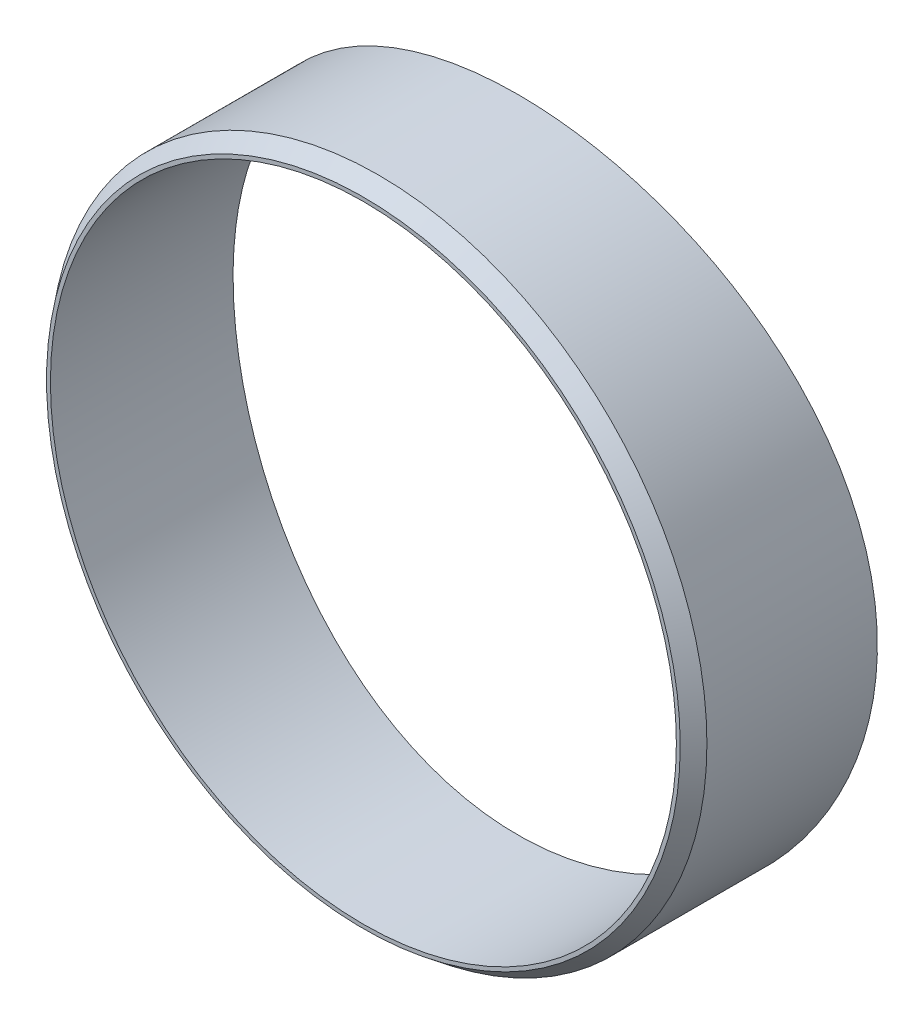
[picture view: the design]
ISO-10303-21;
HEADER;
FILE_DESCRIPTION(('STEP AP214'),'2;1');
FILE_NAME('part.step','',(''),(''),'','','');
FILE_SCHEMA(('AUTOMOTIVE_DESIGN { 1 0 10303 214 1 1 1 1 }'));
ENDSEC;
DATA;
#1=APPLICATION_CONTEXT('core data for automotive mechanical design processes');
#2=APPLICATION_PROTOCOL_DEFINITION('international standard','automotive_design',2000,#1);
#3=PRODUCT_CONTEXT('',#1,'mechanical');
#4=PRODUCT('Part','Part','',(#3));
#5=PRODUCT_RELATED_PRODUCT_CATEGORY('part','',(#4));
#6=PRODUCT_DEFINITION_FORMATION('','',#4);
#7=PRODUCT_DEFINITION_CONTEXT('part definition',#1,'design');
#8=PRODUCT_DEFINITION('design','',#6,#7);
#9=PRODUCT_DEFINITION_SHAPE('','',#8);
#10=(LENGTH_UNIT() NAMED_UNIT(*) SI_UNIT(.MILLI.,.METRE.));
#11=(NAMED_UNIT(*) PLANE_ANGLE_UNIT() SI_UNIT($,.RADIAN.));
#12=(NAMED_UNIT(*) SI_UNIT($,.STERADIAN.) SOLID_ANGLE_UNIT());
#13=UNCERTAINTY_MEASURE_WITH_UNIT(LENGTH_MEASURE(1.E-05),#10,'distance_accuracy_value','');
#14=(GEOMETRIC_REPRESENTATION_CONTEXT(3) GLOBAL_UNCERTAINTY_ASSIGNED_CONTEXT((#13)) GLOBAL_UNIT_ASSIGNED_CONTEXT((#10,
#11,#12)) REPRESENTATION_CONTEXT('',''));
#15=CARTESIAN_POINT('',(0.,0.,0.));
#16=DIRECTION('',(0.,0.,1.));
#17=DIRECTION('',(1.,0.,0.));
#18=AXIS2_PLACEMENT_3D('',#15,#16,#17);
#19=CARTESIAN_POINT('',(0.,0.,63.5));
#20=DIRECTION('',(0.,0.,1.));
#21=DIRECTION('',(1.,0.,0.));
#22=AXIS2_PLACEMENT_3D('',#19,#20,#21);
#23=PLANE('',#22);
#24=CARTESIAN_POINT('',(0.,0.,63.5));
#25=DIRECTION('',(0.,0.,1.));
#26=DIRECTION('',(1.,0.,0.));
#27=AXIS2_PLACEMENT_3D('',#24,#25,#26);
#28=CIRCLE('',#27,128.5875);
#29=CARTESIAN_POINT('',(128.5875,0.,63.5));
#30=VERTEX_POINT('',#29);
#31=EDGE_CURVE('E10',#30,#30,#28,.T.);
#32=ORIENTED_EDGE('',*,*,#31,.F.);
#33=EDGE_LOOP('',(#32));
#34=FACE_BOUND('',#33,.T.);
#35=CARTESIAN_POINT('',(0.,0.,63.5));
#36=DIRECTION('',(0.,0.,1.));
#37=DIRECTION('',(1.,0.,0.));
#38=AXIS2_PLACEMENT_3D('',#35,#36,#37);
#39=CIRCLE('',#38,130.175);
#40=CARTESIAN_POINT('',(130.175,0.,63.5));
#41=VERTEX_POINT('',#40);
#42=EDGE_CURVE('E55',#41,#41,#39,.T.);
#43=ORIENTED_EDGE('',*,*,#42,.T.);
#44=EDGE_LOOP('',(#43));
#45=FACE_BOUND('',#44,.T.);
#46=ADVANCED_FACE('F32',(#34,#45),#23,.T.);
#47=CARTESIAN_POINT('',(0.,0.,63.5));
#48=DIRECTION('',(0.,0.,-1.));
#49=DIRECTION('',(-1.,0.,0.));
#50=AXIS2_PLACEMENT_3D('',#47,#48,#49);
#51=CYLINDRICAL_SURFACE('',#50,134.9375);
#52=CARTESIAN_POINT('',(0.,134.9375,0.));
#53=CARTESIAN_POINT('',(-1.87618329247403,134.937498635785,-6.00693333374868E-07));
#54=CARTESIAN_POINT('',(-3.75243126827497,134.898361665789,-0.00733083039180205));
#55=CARTESIAN_POINT('',(-7.50173863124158,134.741878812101,-0.0366034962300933));
#56=CARTESIAN_POINT('',(-9.3747976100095,134.624523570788,-0.0585476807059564));
#57=CARTESIAN_POINT('',(-13.1149138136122,134.311767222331,-0.116906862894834));
#58=CARTESIAN_POINT('',(-14.9819683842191,134.11633539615,-0.153327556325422));
#59=CARTESIAN_POINT('',(-18.7059824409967,133.647810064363,-0.240384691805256));
#60=CARTESIAN_POINT('',(-20.5629418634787,133.374716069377,-0.291021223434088));
#61=CARTESIAN_POINT('',(-24.2667996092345,132.750836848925,-0.406259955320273));
#62=CARTESIAN_POINT('',(-26.1136735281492,132.399911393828,-0.47088735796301));
#63=CARTESIAN_POINT('',(-29.790668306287,131.621338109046,-0.613601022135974));
#64=CARTESIAN_POINT('',(-31.6207890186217,131.193689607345,-0.691687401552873));
#65=CARTESIAN_POINT('',(-35.2607158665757,130.262578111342,-0.860758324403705));
#66=CARTESIAN_POINT('',(-37.0705252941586,129.759127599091,-0.951740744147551));
#67=CARTESIAN_POINT('',(-40.6671072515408,128.677278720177,-1.14598722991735));
#68=CARTESIAN_POINT('',(-42.4538777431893,128.098873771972,-1.24925237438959));
#69=CARTESIAN_POINT('',(-45.998672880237,126.86908876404,-1.46719036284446));
#70=CARTESIAN_POINT('',(-47.756733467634,126.217809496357,-1.58184742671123));
#71=CARTESIAN_POINT('',(-51.2435747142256,124.842849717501,-1.82189411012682));
#72=CARTESIAN_POINT('',(-52.9723552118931,124.119168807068,-1.94728378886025));
#73=CARTESIAN_POINT('',(-56.3976938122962,122.600729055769,-2.20793264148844));
#74=CARTESIAN_POINT('',(-58.0942512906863,121.805968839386,-2.34319200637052));
#75=CARTESIAN_POINT('',(-61.4522323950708,120.146823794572,-2.62264840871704));
#76=CARTESIAN_POINT('',(-63.1136557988,119.282438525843,-2.7668455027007));
#77=CARTESIAN_POINT('',(-66.3978539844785,117.485980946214,-3.06312421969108));
#78=CARTESIAN_POINT('',(-68.0206448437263,116.553937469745,-3.21520247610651));
#79=CARTESIAN_POINT('',(-71.2257206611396,114.623408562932,-3.52627235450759));
#80=CARTESIAN_POINT('',(-72.8080021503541,113.624917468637,-3.68526456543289));
#81=CARTESIAN_POINT('',(-75.9291359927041,111.563402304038,-4.00904974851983));
#82=CARTESIAN_POINT('',(-77.4679922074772,110.500383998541,-4.17384220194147));
#83=CARTESIAN_POINT('',(-80.5000077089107,108.31146811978,-4.5081327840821));
#84=CARTESIAN_POINT('',(-81.9931626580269,107.185564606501,-4.67763135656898));
#85=CARTESIAN_POINT('',(-84.9468830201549,104.860508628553,-5.02199797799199));
#86=CARTESIAN_POINT('',(-86.4069282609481,103.660700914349,-5.19690408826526));
#87=CARTESIAN_POINT('',(-89.275349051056,101.200845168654,-5.54912934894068));
#88=CARTESIAN_POINT('',(-90.6837186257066,99.940790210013,-5.72644877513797));
#89=CARTESIAN_POINT('',(-93.4462375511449,97.3627192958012,-6.08224595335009));
#90=CARTESIAN_POINT('',(-94.800386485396,96.0447028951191,-6.26072371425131));
#91=CARTESIAN_POINT('',(-97.4520009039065,93.3531196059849,-6.6175692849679));
#92=CARTESIAN_POINT('',(-98.7494728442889,91.979559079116,-6.7959371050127));
#93=CARTESIAN_POINT('',(-101.285971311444,89.1787603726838,-7.15137512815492));
#94=CARTESIAN_POINT('',(-102.524984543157,87.7515101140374,-7.32844502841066));
#95=CARTESIAN_POINT('',(-104.942009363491,84.8461783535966,-7.67998626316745));
#96=CARTESIAN_POINT('',(-106.120026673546,83.3681016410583,-7.8544578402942));
#97=CARTESIAN_POINT('',(-108.413251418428,80.3633498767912,-8.19960590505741));
#98=CARTESIAN_POINT('',(-109.528452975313,78.8366702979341,-8.37028203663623));
#99=CARTESIAN_POINT('',(-111.69388157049,75.7375653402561,-8.70659929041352));
#100=CARTESIAN_POINT('',(-112.744114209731,74.1651439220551,-8.87224084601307));
#101=CARTESIAN_POINT('',(-114.785927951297,70.9644387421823,-9.19861694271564));
#102=CARTESIAN_POINT('',(-115.776977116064,69.335810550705,-9.35930207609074));
#103=CARTESIAN_POINT('',(-117.689473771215,66.0374952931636,-9.6732068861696));
#104=CARTESIAN_POINT('',(-118.610921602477,64.3678084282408,-9.82642659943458));
#105=CARTESIAN_POINT('',(-120.382533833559,60.9902542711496,-10.1242836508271));
#106=CARTESIAN_POINT('',(-121.23269722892,59.2823864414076,-10.2689208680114));
#107=CARTESIAN_POINT('',(-122.860130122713,55.8315017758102,-10.5485460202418));
#108=CARTESIAN_POINT('',(-123.637400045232,54.088485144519,-10.6835340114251));
#109=CARTESIAN_POINT('',(-125.117557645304,50.5704210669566,-10.9428595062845));
#110=CARTESIAN_POINT('',(-125.820447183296,48.7953744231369,-11.0671972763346));
#111=CARTESIAN_POINT('',(-127.150452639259,45.2165368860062,-11.3042896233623));
#112=CARTESIAN_POINT('',(-127.777575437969,43.4127486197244,-11.4170452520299));
#113=CARTESIAN_POINT('',(-128.954918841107,39.7794505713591,-11.6301456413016));
#114=CARTESIAN_POINT('',(-129.505136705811,37.9499398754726,-11.7304899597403));
#115=CARTESIAN_POINT('',(-130.527555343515,34.2685805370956,-11.9180071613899));
#116=CARTESIAN_POINT('',(-130.999756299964,32.4167319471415,-12.0051800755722));
#117=CARTESIAN_POINT('',(-131.86020573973,28.7155546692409,-12.1647689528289));
#118=CARTESIAN_POINT('',(-132.249359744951,26.8664432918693,-12.2373435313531));
#119=CARTESIAN_POINT('',(-132.949750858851,23.1530265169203,-12.3684398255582));
#120=CARTESIAN_POINT('',(-133.260988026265,21.2887211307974,-12.4269615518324));
#121=CARTESIAN_POINT('',(-133.804923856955,17.5483016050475,-12.5295152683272));
#122=CARTESIAN_POINT('',(-134.037622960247,15.6721875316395,-12.5735473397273));
#123=CARTESIAN_POINT('',(-134.424018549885,11.9115515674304,-12.6467927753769));
#124=CARTESIAN_POINT('',(-134.577715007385,10.0270296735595,-12.6760061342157));
#125=CARTESIAN_POINT('',(-134.805786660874,6.25316240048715,-12.7193933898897));
#126=CARTESIAN_POINT('',(-134.88016787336,4.36381739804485,-12.7335684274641));
#127=CARTESIAN_POINT('',(-134.949479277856,0.583620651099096,-12.746776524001));
#128=CARTESIAN_POINT('',(-134.944409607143,-1.30723109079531,-12.7458096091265));
#129=CARTESIAN_POINT('',(-134.854830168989,-5.08697262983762,-12.7287411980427));
#130=CARTESIAN_POINT('',(-134.770320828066,-6.97586243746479,-12.7126397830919));
#131=CARTESIAN_POINT('',(-134.522033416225,-10.7482333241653,-12.6654233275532));
#132=CARTESIAN_POINT('',(-134.358255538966,-12.6317144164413,-12.6343083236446));
#133=CARTESIAN_POINT('',(-133.954446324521,-16.3650141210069,-12.5578067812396));
#134=CARTESIAN_POINT('',(-133.715450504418,-18.214948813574,-12.5126141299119));
#135=CARTESIAN_POINT('',(-133.161034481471,-21.9030943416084,-12.4081612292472));
#136=CARTESIAN_POINT('',(-132.845607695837,-23.7413041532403,-12.3488997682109));
#137=CARTESIAN_POINT('',(-132.138972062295,-27.4024942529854,-12.2167453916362));
#138=CARTESIAN_POINT('',(-131.747767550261,-29.2254754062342,-12.1438532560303));
#139=CARTESIAN_POINT('',(-130.89031400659,-32.8531339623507,-11.9849620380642));
#140=CARTESIAN_POINT('',(-130.424064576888,-34.6578112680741,-11.89896288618));
#141=CARTESIAN_POINT('',(-129.417394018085,-38.2457690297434,-11.7144742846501));
#142=CARTESIAN_POINT('',(-128.876970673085,-40.0290488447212,-11.6159844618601));
#143=CARTESIAN_POINT('',(-127.722975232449,-43.5710910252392,-11.4072214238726));
#144=CARTESIAN_POINT('',(-127.109402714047,-45.3298532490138,-11.2969481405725));
#145=CARTESIAN_POINT('',(-125.810275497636,-48.8197723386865,-11.0654087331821));
#146=CARTESIAN_POINT('',(-125.124723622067,-50.5509302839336,-10.944143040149));
#147=CARTESIAN_POINT('',(-123.682810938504,-53.982922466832,-10.6914630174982));
#148=CARTESIAN_POINT('',(-122.926443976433,-55.683754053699,-10.5600478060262));
#149=CARTESIAN_POINT('',(-121.339638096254,-59.0620384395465,-10.2871985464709));
#150=CARTESIAN_POINT('',(-120.508787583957,-60.739293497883,-10.145709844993));
#151=CARTESIAN_POINT('',(-118.778288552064,-64.0573844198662,-9.85439737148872));
#152=CARTESIAN_POINT('',(-117.878633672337,-65.6982168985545,-9.70457282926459));
#153=CARTESIAN_POINT('',(-116.012238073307,-68.9404689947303,-9.39766286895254));
#154=CARTESIAN_POINT('',(-115.045500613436,-70.5418905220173,-9.24057780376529));
#155=CARTESIAN_POINT('',(-113.046590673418,-73.702740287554,-8.92023851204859));
#156=CARTESIAN_POINT('',(-112.014417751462,-75.2621682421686,-8.75698424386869));
#157=CARTESIAN_POINT('',(-109.886424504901,-78.3364379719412,-8.42544303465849));
#158=CARTESIAN_POINT('',(-108.790603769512,-79.8512794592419,-8.2571560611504));
#159=CARTESIAN_POINT('',(-106.537199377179,-82.8338545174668,-7.9167164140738));
#160=CARTESIAN_POINT('',(-105.379615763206,-84.3015881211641,-7.74456374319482));
#161=CARTESIAN_POINT('',(-103.004635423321,-87.1875353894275,-7.39757805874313));
#162=CARTESIAN_POINT('',(-101.787238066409,-88.6057485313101,-7.22274501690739));
#163=CARTESIAN_POINT('',(-99.2946956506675,-91.3902835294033,-6.87160258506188));
#164=CARTESIAN_POINT('',(-98.0195508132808,-92.7566055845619,-6.69529320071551));
#165=CARTESIAN_POINT('',(-95.3933070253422,-95.4559946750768,-6.33965180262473));
#166=CARTESIAN_POINT('',(-94.041333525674,-96.78821045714,-6.16031554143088));
#167=CARTESIAN_POINT('',(-91.2824572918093,-99.3943784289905,-5.8026453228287));
#168=CARTESIAN_POINT('',(-89.875559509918,-100.668335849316,-5.62431127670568));
#169=CARTESIAN_POINT('',(-87.0089687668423,-103.156047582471,-5.26986452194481));
#170=CARTESIAN_POINT('',(-85.5492701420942,-104.369795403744,-5.09375205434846));
#171=CARTESIAN_POINT('',(-82.5798438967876,-106.734720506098,-4.74502156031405));
#172=CARTESIAN_POINT('',(-81.0701206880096,-107.885903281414,-4.57240322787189));
#173=CARTESIAN_POINT('',(-78.0023245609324,-110.124355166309,-4.23177185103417));
#174=CARTESIAN_POINT('',(-76.4442275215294,-111.211591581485,-4.06376118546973));
#175=CARTESIAN_POINT('',(-73.2830935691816,-113.319575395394,-3.73361986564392));
#176=CARTESIAN_POINT('',(-71.6800569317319,-114.340323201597,-3.57148917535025));
#177=CARTESIAN_POINT('',(-68.4318338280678,-116.313472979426,-3.25425319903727));
#178=CARTESIAN_POINT('',(-66.786648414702,-117.265876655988,-3.09914773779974));
#179=CARTESIAN_POINT('',(-63.4569452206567,-119.100622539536,-2.79705361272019));
#180=CARTESIAN_POINT('',(-61.7724276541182,-119.982965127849,-2.65006490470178));
#181=CARTESIAN_POINT('',(-58.3634837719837,-121.677702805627,-2.36495038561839));
#182=CARTESIAN_POINT('',(-56.6389825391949,-122.489950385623,-2.22684341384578));
#183=CARTESIAN_POINT('',(-53.1566163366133,-124.040863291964,-1.96081833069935));
#184=CARTESIAN_POINT('',(-51.3987543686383,-124.779535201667,-1.83289930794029));
#185=CARTESIAN_POINT('',(-47.8523315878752,-126.182090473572,-1.58812864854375));
#186=CARTESIAN_POINT('',(-46.0637655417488,-126.845960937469,-1.47127892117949));
#187=CARTESIAN_POINT('',(-42.4594474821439,-128.097476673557,-1.24950984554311));
#188=CARTESIAN_POINT('',(-40.643695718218,-128.685122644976,-1.1445903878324));
#189=CARTESIAN_POINT('',(-36.9917690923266,-129.781993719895,-0.947623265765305));
#190=CARTESIAN_POINT('',(-35.1556399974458,-130.29136683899,-0.855551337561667));
#191=CARTESIAN_POINT('',(-31.4628853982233,-131.2320311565,-0.684703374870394));
#192=CARTESIAN_POINT('',(-29.6062600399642,-131.663322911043,-0.605927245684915));
#193=CARTESIAN_POINT('',(-25.8766683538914,-132.446806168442,-0.462266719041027));
#194=CARTESIAN_POINT('',(-24.0037090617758,-132.799030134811,-0.397376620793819));
#195=CARTESIAN_POINT('',(-20.2443184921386,-133.423860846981,-0.281921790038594));
#196=CARTESIAN_POINT('',(-18.3578889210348,-133.696477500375,-0.231355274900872));
#197=CARTESIAN_POINT('',(-15.1011420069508,-134.096893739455,-0.156927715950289));
#198=CARTESIAN_POINT('',(-13.7332304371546,-134.243882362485,-0.12955078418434));
#199=CARTESIAN_POINT('',(-10.9937162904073,-134.49594299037,-0.0825505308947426));
#200=CARTESIAN_POINT('',(-9.62211463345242,-134.601024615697,-0.0629254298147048));
#201=CARTESIAN_POINT('',(-6.87624752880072,-134.769203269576,-0.0314950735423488));
#202=CARTESIAN_POINT('',(-5.50198207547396,-134.832300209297,-0.0196898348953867));
#203=CARTESIAN_POINT('',(-2.75182287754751,-134.916453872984,-0.00394118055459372));
#204=CARTESIAN_POINT('',(-1.37592883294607,-134.937501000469,4.40528023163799E-07));
#205=CARTESIAN_POINT('',(1.87618329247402,-134.937498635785,-6.00693309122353E-07));
#206=CARTESIAN_POINT('',(3.75243126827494,-134.898361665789,-0.00733083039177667));
#207=CARTESIAN_POINT('',(7.50173863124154,-134.741878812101,-0.0366034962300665));
#208=CARTESIAN_POINT('',(9.37479761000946,-134.624523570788,-0.0585476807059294));
#209=CARTESIAN_POINT('',(13.1149138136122,-134.311767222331,-0.116906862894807));
#210=CARTESIAN_POINT('',(14.9819683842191,-134.11633539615,-0.153327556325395));
#211=CARTESIAN_POINT('',(18.7059824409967,-133.647810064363,-0.240384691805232));
#212=CARTESIAN_POINT('',(20.5629418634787,-133.374716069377,-0.291021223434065));
#213=CARTESIAN_POINT('',(24.2667996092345,-132.750836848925,-0.406259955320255));
#214=CARTESIAN_POINT('',(26.1136735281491,-132.399911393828,-0.470887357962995));
#215=CARTESIAN_POINT('',(29.790668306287,-131.621338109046,-0.613601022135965));
#216=CARTESIAN_POINT('',(31.6207890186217,-131.193689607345,-0.691687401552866));
#217=CARTESIAN_POINT('',(35.2607158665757,-130.262578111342,-0.86075832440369));
#218=CARTESIAN_POINT('',(37.0705252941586,-129.759127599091,-0.951740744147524));
#219=CARTESIAN_POINT('',(40.6671072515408,-128.677278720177,-1.14598722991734));
#220=CARTESIAN_POINT('',(42.4538777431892,-128.098873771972,-1.2492523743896));
#221=CARTESIAN_POINT('',(45.998672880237,-126.86908876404,-1.46719036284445));
#222=CARTESIAN_POINT('',(47.756733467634,-126.217809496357,-1.58184742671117));
#223=CARTESIAN_POINT('',(51.2435747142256,-124.842849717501,-1.82189411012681));
#224=CARTESIAN_POINT('',(52.9723552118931,-124.119168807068,-1.94728378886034));
#225=CARTESIAN_POINT('',(56.3976938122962,-122.600729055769,-2.20793264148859));
#226=CARTESIAN_POINT('',(58.0942512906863,-121.805968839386,-2.34319200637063));
#227=CARTESIAN_POINT('',(61.4522323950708,-120.146823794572,-2.62264840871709));
#228=CARTESIAN_POINT('',(63.1136557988,-119.282438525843,-2.76684550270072));
#229=CARTESIAN_POINT('',(66.3978539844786,-117.485980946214,-3.06312421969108));
#230=CARTESIAN_POINT('',(68.0206448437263,-116.553937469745,-3.2152024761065));
#231=CARTESIAN_POINT('',(71.2257206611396,-114.623408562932,-3.52627235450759));
#232=CARTESIAN_POINT('',(72.8080021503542,-113.624917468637,-3.68526456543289));
#233=CARTESIAN_POINT('',(75.9291359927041,-111.563402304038,-4.00904974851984));
#234=CARTESIAN_POINT('',(77.4679922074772,-110.500383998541,-4.17384220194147));
#235=CARTESIAN_POINT('',(80.5000077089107,-108.31146811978,-4.50813278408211));
#236=CARTESIAN_POINT('',(81.9931626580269,-107.185564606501,-4.67763135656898));
#237=CARTESIAN_POINT('',(84.9468830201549,-104.860508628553,-5.02199797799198));
#238=CARTESIAN_POINT('',(86.4069282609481,-103.660700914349,-5.19690408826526));
#239=CARTESIAN_POINT('',(89.275349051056,-101.200845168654,-5.54912934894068));
#240=CARTESIAN_POINT('',(90.6837186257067,-99.940790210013,-5.72644877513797));
#241=CARTESIAN_POINT('',(93.4462375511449,-97.3627192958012,-6.0822459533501));
#242=CARTESIAN_POINT('',(94.800386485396,-96.0447028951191,-6.26072371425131));
#243=CARTESIAN_POINT('',(97.4520009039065,-93.3531196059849,-6.61756928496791));
#244=CARTESIAN_POINT('',(98.7494728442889,-91.979559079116,-6.79593710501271));
#245=CARTESIAN_POINT('',(101.285971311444,-89.1787603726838,-7.15137512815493));
#246=CARTESIAN_POINT('',(102.524984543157,-87.7515101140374,-7.32844502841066));
#247=CARTESIAN_POINT('',(104.942009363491,-84.8461783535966,-7.67998626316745));
#248=CARTESIAN_POINT('',(106.120026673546,-83.3681016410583,-7.8544578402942));
#249=CARTESIAN_POINT('',(108.413251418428,-80.3633498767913,-8.19960590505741));
#250=CARTESIAN_POINT('',(109.528452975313,-78.8366702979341,-8.37028203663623));
#251=CARTESIAN_POINT('',(111.69388157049,-75.7375653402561,-8.70659929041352));
#252=CARTESIAN_POINT('',(112.744114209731,-74.1651439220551,-8.87224084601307));
#253=CARTESIAN_POINT('',(114.785927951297,-70.9644387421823,-9.19861694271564));
#254=CARTESIAN_POINT('',(115.776977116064,-69.335810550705,-9.35930207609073));
#255=CARTESIAN_POINT('',(117.689473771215,-66.0374952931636,-9.67320688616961));
#256=CARTESIAN_POINT('',(118.610921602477,-64.3678084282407,-9.82642659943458));
#257=CARTESIAN_POINT('',(120.382533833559,-60.9902542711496,-10.1242836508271));
#258=CARTESIAN_POINT('',(121.23269722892,-59.2823864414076,-10.2689208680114));
#259=CARTESIAN_POINT('',(122.860130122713,-55.8315017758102,-10.5485460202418));
#260=CARTESIAN_POINT('',(123.637400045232,-54.088485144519,-10.6835340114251));
#261=CARTESIAN_POINT('',(125.117557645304,-50.5704210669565,-10.9428595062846));
#262=CARTESIAN_POINT('',(125.820447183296,-48.7953744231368,-11.0671972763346));
#263=CARTESIAN_POINT('',(127.150452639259,-45.2165368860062,-11.3042896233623));
#264=CARTESIAN_POINT('',(127.777575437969,-43.4127486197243,-11.4170452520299));
#265=CARTESIAN_POINT('',(128.954918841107,-39.779450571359,-11.6301456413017));
#266=CARTESIAN_POINT('',(129.505136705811,-37.9499398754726,-11.7304899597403));
#267=CARTESIAN_POINT('',(130.527555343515,-34.2685805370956,-11.9180071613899));
#268=CARTESIAN_POINT('',(130.999756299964,-32.4167319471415,-12.0051800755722));
#269=CARTESIAN_POINT('',(131.86020573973,-28.7155546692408,-12.1647689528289));
#270=CARTESIAN_POINT('',(132.249359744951,-26.8664432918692,-12.2373435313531));
#271=CARTESIAN_POINT('',(132.949750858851,-23.1530265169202,-12.3684398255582));
#272=CARTESIAN_POINT('',(133.260988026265,-21.2887211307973,-12.4269615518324));
#273=CARTESIAN_POINT('',(133.804923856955,-17.5483016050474,-12.5295152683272));
#274=CARTESIAN_POINT('',(134.037622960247,-15.6721875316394,-12.5735473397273));
#275=CARTESIAN_POINT('',(134.424018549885,-11.9115515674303,-12.6467927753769));
#276=CARTESIAN_POINT('',(134.577715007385,-10.0270296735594,-12.6760061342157));
#277=CARTESIAN_POINT('',(134.805786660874,-6.2531624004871,-12.7193933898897));
#278=CARTESIAN_POINT('',(134.88016787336,-4.36381739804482,-12.7335684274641));
#279=CARTESIAN_POINT('',(134.949479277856,-0.58362065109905,-12.746776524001));
#280=CARTESIAN_POINT('',(134.944409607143,1.30723109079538,-12.7458096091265));
#281=CARTESIAN_POINT('',(134.854830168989,5.08697262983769,-12.7287411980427));
#282=CARTESIAN_POINT('',(134.770320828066,6.97586243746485,-12.7126397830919));
#283=CARTESIAN_POINT('',(134.522033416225,10.7482333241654,-12.6654233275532));
#284=CARTESIAN_POINT('',(134.358255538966,12.6317144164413,-12.6343083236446));
#285=CARTESIAN_POINT('',(133.954446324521,16.3650141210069,-12.5578067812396));
#286=CARTESIAN_POINT('',(133.715450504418,18.2149488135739,-12.5126141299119));
#287=CARTESIAN_POINT('',(133.161034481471,21.9030943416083,-12.4081612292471));
#288=CARTESIAN_POINT('',(132.845607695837,23.7413041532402,-12.3488997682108));
#289=CARTESIAN_POINT('',(132.138972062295,27.4024942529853,-12.2167453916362));
#290=CARTESIAN_POINT('',(131.747767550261,29.2254754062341,-12.1438532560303));
#291=CARTESIAN_POINT('',(130.89031400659,32.8531339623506,-11.9849620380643));
#292=CARTESIAN_POINT('',(130.424064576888,34.657811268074,-11.89896288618));
#293=CARTESIAN_POINT('',(129.417394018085,38.2457690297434,-11.7144742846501));
#294=CARTESIAN_POINT('',(128.876970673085,40.0290488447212,-11.6159844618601));
#295=CARTESIAN_POINT('',(127.722975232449,43.5710910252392,-11.4072214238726));
#296=CARTESIAN_POINT('',(127.109402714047,45.3298532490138,-11.2969481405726));
#297=CARTESIAN_POINT('',(125.810275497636,48.8197723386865,-11.0654087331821));
#298=CARTESIAN_POINT('',(125.124723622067,50.5509302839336,-10.944143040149));
#299=CARTESIAN_POINT('',(123.682810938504,53.982922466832,-10.6914630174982));
#300=CARTESIAN_POINT('',(122.926443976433,55.683754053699,-10.5600478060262));
#301=CARTESIAN_POINT('',(121.339638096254,59.0620384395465,-10.2871985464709));
#302=CARTESIAN_POINT('',(120.508787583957,60.7392934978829,-10.145709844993));
#303=CARTESIAN_POINT('',(118.778288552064,64.0573844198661,-9.85439737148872));
#304=CARTESIAN_POINT('',(117.878633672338,65.6982168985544,-9.70457282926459));
#305=CARTESIAN_POINT('',(116.012238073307,68.9404689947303,-9.39766286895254));
#306=CARTESIAN_POINT('',(115.045500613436,70.5418905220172,-9.24057780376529));
#307=CARTESIAN_POINT('',(113.046590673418,73.702740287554,-8.9202385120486));
#308=CARTESIAN_POINT('',(112.014417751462,75.2621682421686,-8.7569842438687));
#309=CARTESIAN_POINT('',(109.886424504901,78.3364379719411,-8.4254430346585));
#310=CARTESIAN_POINT('',(108.790603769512,79.8512794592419,-8.25715606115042));
#311=CARTESIAN_POINT('',(106.537199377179,82.8338545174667,-7.91671641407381));
#312=CARTESIAN_POINT('',(105.379615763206,84.301588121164,-7.74456374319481));
#313=CARTESIAN_POINT('',(103.004635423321,87.1875353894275,-7.39757805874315));
#314=CARTESIAN_POINT('',(101.787238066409,88.60574853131,-7.22274501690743));
#315=CARTESIAN_POINT('',(99.2946956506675,91.3902835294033,-6.87160258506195));
#316=CARTESIAN_POINT('',(98.0195508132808,92.7566055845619,-6.69529320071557));
#317=CARTESIAN_POINT('',(95.3933070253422,95.4559946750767,-6.33965180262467));
#318=CARTESIAN_POINT('',(94.0413335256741,96.7882104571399,-6.16031554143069));
#319=CARTESIAN_POINT('',(91.2824572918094,99.3943784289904,-5.80264532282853));
#320=CARTESIAN_POINT('',(89.8755595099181,100.668335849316,-5.62431127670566));
#321=CARTESIAN_POINT('',(87.0089687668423,103.156047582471,-5.26986452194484));
#322=CARTESIAN_POINT('',(85.5492701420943,104.369795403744,-5.09375205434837));
#323=CARTESIAN_POINT('',(82.5798438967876,106.734720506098,-4.74502156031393));
#324=CARTESIAN_POINT('',(81.0701206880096,107.885903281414,-4.57240322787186));
#325=CARTESIAN_POINT('',(78.0023245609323,110.124355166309,-4.2317718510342));
#326=CARTESIAN_POINT('',(76.4442275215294,111.211591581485,-4.06376118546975));
#327=CARTESIAN_POINT('',(73.2830935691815,113.319575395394,-3.73361986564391));
#328=CARTESIAN_POINT('',(71.6800569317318,114.340323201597,-3.57148917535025));
#329=CARTESIAN_POINT('',(68.4318338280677,116.313472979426,-3.25425319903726));
#330=CARTESIAN_POINT('',(66.7866484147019,117.265876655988,-3.09914773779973));
#331=CARTESIAN_POINT('',(63.4569452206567,119.100622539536,-2.79705361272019));
#332=CARTESIAN_POINT('',(61.7724276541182,119.982965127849,-2.65006490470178));
#333=CARTESIAN_POINT('',(58.3634837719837,121.677702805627,-2.36495038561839));
#334=CARTESIAN_POINT('',(56.6389825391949,122.489950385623,-2.22684341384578));
#335=CARTESIAN_POINT('',(53.1566163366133,124.040863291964,-1.96081833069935));
#336=CARTESIAN_POINT('',(51.3987543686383,124.779535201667,-1.83289930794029));
#337=CARTESIAN_POINT('',(47.8523315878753,126.182090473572,-1.58812864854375));
#338=CARTESIAN_POINT('',(46.0637655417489,126.845960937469,-1.47127892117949));
#339=CARTESIAN_POINT('',(42.459447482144,128.097476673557,-1.24950984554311));
#340=CARTESIAN_POINT('',(40.643695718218,128.685122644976,-1.1445903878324));
#341=CARTESIAN_POINT('',(36.9917690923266,129.781993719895,-0.947623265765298));
#342=CARTESIAN_POINT('',(35.1556399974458,130.29136683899,-0.855551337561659));
#343=CARTESIAN_POINT('',(31.4628853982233,131.2320311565,-0.684703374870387));
#344=CARTESIAN_POINT('',(29.6062600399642,131.663322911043,-0.605927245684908));
#345=CARTESIAN_POINT('',(25.8766683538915,132.446806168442,-0.462266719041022));
#346=CARTESIAN_POINT('',(24.0037090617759,132.799030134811,-0.397376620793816));
#347=CARTESIAN_POINT('',(20.2443184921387,133.423860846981,-0.281921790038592));
#348=CARTESIAN_POINT('',(18.3578889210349,133.696477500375,-0.23135527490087));
#349=CARTESIAN_POINT('',(15.1011420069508,134.096893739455,-0.156927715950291));
#350=CARTESIAN_POINT('',(13.7332304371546,134.243882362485,-0.129550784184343));
#351=CARTESIAN_POINT('',(10.9937162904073,134.49594299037,-0.0825505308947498));
#352=CARTESIAN_POINT('',(9.62211463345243,134.601024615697,-0.0629254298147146));
#353=CARTESIAN_POINT('',(6.87624752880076,134.769203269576,-0.0314950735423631));
#354=CARTESIAN_POINT('',(5.50198207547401,134.832300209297,-0.019689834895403));
#355=CARTESIAN_POINT('',(2.75182287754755,134.916453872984,-0.00394118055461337));
#356=CARTESIAN_POINT('',(1.37592883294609,134.937501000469,4.40528001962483E-07));
#357=CARTESIAN_POINT('',(0.,134.9375,0.));
#358=B_SPLINE_CURVE_WITH_KNOTS('',3,(#52,#53,#54,#55,#56,#57,#58,#59,#60,#61,#62,#63,#64,#65,
#66,#67,#68,#69,#70,#71,#72,#73,#74,#75,#76,#77,#78,#79,#80,#81,#82,#83,#84,#85,#86,#87,#88,#89,
#90,#91,#92,#93,#94,#95,#96,#97,#98,#99,#100,#101,#102,#103,#104,#105,#106,#107,#108,#109,#110,
#111,#112,#113,#114,#115,#116,#117,#118,#119,#120,#121,#122,#123,#124,#125,#126,#127,#128,#129,
#130,#131,#132,#133,#134,#135,#136,#137,#138,#139,#140,#141,#142,#143,#144,#145,#146,#147,#148,
#149,#150,#151,#152,#153,#154,#155,#156,#157,#158,#159,#160,#161,#162,#163,#164,#165,#166,#167,
#168,#169,#170,#171,#172,#173,#174,#175,#176,#177,#178,#179,#180,#181,#182,#183,#184,#185,#186,
#187,#188,#189,#190,#191,#192,#193,#194,#195,#196,#197,#198,#199,#200,#201,#202,#203,#204,#205,
#206,#207,#208,#209,#210,#211,#212,#213,#214,#215,#216,#217,#218,#219,#220,#221,#222,#223,#224,
#225,#226,#227,#228,#229,#230,#231,#232,#233,#234,#235,#236,#237,#238,#239,#240,#241,#242,#243,
#244,#245,#246,#247,#248,#249,#250,#251,#252,#253,#254,#255,#256,#257,#258,#259,#260,#261,#262,
#263,#264,#265,#266,#267,#268,#269,#270,#271,#272,#273,#274,#275,#276,#277,#278,#279,#280,#281,
#282,#283,#284,#285,#286,#287,#288,#289,#290,#291,#292,#293,#294,#295,#296,#297,#298,#299,#300,
#301,#302,#303,#304,#305,#306,#307,#308,#309,#310,#311,#312,#313,#314,#315,#316,#317,#318,#319,
#320,#321,#322,#323,#324,#325,#326,#327,#328,#329,#330,#331,#332,#333,#334,#335,#336,#337,#338,
#339,#340,#341,#342,#343,#344,#345,#346,#347,#348,#349,#350,#351,#352,#353,#354,#355,#356,#357),
.UNSPECIFIED.,.T.,.F.,(4,2,2,2,2,2,2,2,2,2,2,2,2,2,2,2,2,2,2,2,2,2,2,2,2,2,2,2,2,2,2,2,2,2,2,2,
2,2,2,2,2,2,2,2,2,2,2,2,2,2,2,2,2,2,2,2,2,2,2,2,2,2,2,2,2,2,2,2,2,2,2,2,2,2,2,2,2,2,2,2,2,2,2,2,
2,2,2,2,2,2,2,2,2,2,2,2,2,2,2,2,2,2,2,2,2,2,2,2,2,2,2,2,2,2,2,2,2,2,2,2,2,2,2,2,2,2,2,2,2,2,2,2,
2,2,2,2,2,2,2,2,2,2,2,2,2,2,2,2,2,2,2,2,4),(0.,5.62823971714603,11.257152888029,
16.8882829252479,22.5194484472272,28.1608433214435,33.8022876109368,39.4428039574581,
45.0838159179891,50.7171200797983,56.3504553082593,61.9838995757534,67.6173794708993,
73.2484724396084,78.880046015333,84.5111172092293,90.1427212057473,95.8346281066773,
101.527191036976,107.21979769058,112.911754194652,118.604999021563,124.297708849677,
129.990950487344,135.683700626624,141.421653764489,147.159578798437,152.897584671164,
158.635557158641,164.373386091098,170.110693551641,175.848205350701,181.585703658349,
187.257023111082,192.928338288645,198.599621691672,204.270907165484,209.941762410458,
215.61260785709,221.283422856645,226.954224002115,232.550139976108,238.146538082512,
243.742616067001,249.338723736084,254.934998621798,260.531305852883,266.127393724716,
271.723968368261,277.353640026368,282.983832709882,288.613752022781,294.243709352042,
299.873703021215,305.503692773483,311.133741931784,316.763769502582,322.481623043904,
328.198962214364,333.916916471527,339.634367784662,345.354717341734,351.075031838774,
356.795203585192,362.51534419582,368.247242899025,373.978628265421,379.711000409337,
385.44331996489,391.164662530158,396.885964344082,402.60491280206,408.323149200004,
412.45070594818,416.577314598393,420.703931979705,424.831491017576,430.459730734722,
436.088643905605,441.719773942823,447.350939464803,452.992334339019,458.633778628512,
464.274294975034,469.915306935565,475.548611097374,481.181946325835,486.815390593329,
492.448870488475,498.079963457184,503.711537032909,509.342608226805,514.974212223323,
520.666119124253,526.358682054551,532.051288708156,537.743245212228,543.436490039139,
549.129199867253,554.82244150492,560.5151916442,566.253144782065,571.991069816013,
577.729075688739,583.467048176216,589.204877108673,594.942184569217,600.679696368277,
606.417194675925,612.088514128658,617.75982930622,623.431112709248,629.10239818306,
634.773253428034,640.444098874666,646.114913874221,651.785715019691,657.381630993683,
662.978029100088,668.574107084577,674.17021475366,679.766489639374,685.362796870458,
690.958884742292,696.555459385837,702.185131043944,707.815323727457,713.445243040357,
719.075200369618,724.705194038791,730.335183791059,735.96523294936,741.595260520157,
747.31311406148,753.03045323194,758.748407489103,764.465858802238,770.18620835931,
775.90652285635,781.626694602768,787.346835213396,793.078733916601,798.810119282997,
804.542491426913,810.274810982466,815.996153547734,821.717455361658,827.436403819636,
833.15464021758,837.282196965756,841.408805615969,845.535422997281,849.662982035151),.UNSPECIFIED.);
#359=CARTESIAN_POINT('',(0.,134.9375,0.));
#360=VERTEX_POINT('',#359);
#361=EDGE_CURVE('E46',#360,#360,#358,.T.);
#362=ORIENTED_EDGE('',*,*,#361,.T.);
#363=EDGE_LOOP('',(#362));
#364=FACE_BOUND('',#363,.T.);
#365=CARTESIAN_POINT('',(0.,0.,57.2933891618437));
#366=DIRECTION('',(0.,0.,1.));
#367=DIRECTION('',(1.,0.,0.));
#368=AXIS2_PLACEMENT_3D('',#365,#366,#367);
#369=CIRCLE('',#368,134.9375);
#370=CARTESIAN_POINT('',(134.9375,0.,57.2933891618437));
#371=VERTEX_POINT('',#370);
#372=EDGE_CURVE('E78',#371,#371,#369,.T.);
#373=ORIENTED_EDGE('',*,*,#372,.F.);
#374=EDGE_LOOP('',(#373));
#375=FACE_BOUND('',#374,.T.);
#376=ADVANCED_FACE('F34',(#364,#375),#51,.T.);
#377=CARTESIAN_POINT('',(0.,0.,63.5));
#378=DIRECTION('',(0.,0.,-1.));
#379=DIRECTION('',(-1.,0.,0.));
#380=AXIS2_PLACEMENT_3D('',#377,#378,#379);
#381=CYLINDRICAL_SURFACE('',#380,128.5875);
#382=CARTESIAN_POINT('',(-128.5875,0.,-11.5636781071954));
#383=CARTESIAN_POINT('',(-128.587503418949,-1.79077204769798,-11.5636798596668));
#384=CARTESIAN_POINT('',(-128.550088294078,-3.58144937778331,-11.5568917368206));
#385=CARTESIAN_POINT('',(-128.400519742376,-7.15939113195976,-11.5297953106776));
#386=CARTESIAN_POINT('',(-128.288376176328,-8.94665597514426,-11.5094887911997));
#387=CARTESIAN_POINT('',(-127.989542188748,-12.5151515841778,-11.4554985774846));
#388=CARTESIAN_POINT('',(-127.802834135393,-14.2963808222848,-11.4218117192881));
#389=CARTESIAN_POINT('',(-127.355231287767,-17.8492607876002,-11.3413080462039));
#390=CARTESIAN_POINT('',(-127.094333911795,-19.6209111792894,-11.2944907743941));
#391=CARTESIAN_POINT('',(-126.498631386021,-23.1527790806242,-11.1880288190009));
#392=CARTESIAN_POINT('',(-126.163768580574,-24.9129865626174,-11.1283741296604));
#393=CARTESIAN_POINT('',(-125.420901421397,-28.4174404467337,-10.9966960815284));
#394=CARTESIAN_POINT('',(-125.012896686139,-30.1616867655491,-10.9246726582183));
#395=CARTESIAN_POINT('',(-124.124555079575,-33.6310303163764,-10.7687874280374));
#396=CARTESIAN_POINT('',(-123.644221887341,-35.3561285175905,-10.684926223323));
#397=CARTESIAN_POINT('',(-122.612122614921,-38.7842344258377,-10.5059723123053));
#398=CARTESIAN_POINT('',(-122.060356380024,-40.487242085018,-10.4108795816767));
#399=CARTESIAN_POINT('',(-120.886979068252,-43.8666127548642,-10.2102444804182));
#400=CARTESIAN_POINT('',(-120.265433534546,-45.5429991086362,-10.104711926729));
#401=CARTESIAN_POINT('',(-118.95318037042,-48.8679927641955,-9.88387204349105));
#402=CARTESIAN_POINT('',(-118.262466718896,-50.5165976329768,-9.7685638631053));
#403=CARTESIAN_POINT('',(-116.813250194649,-53.7829131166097,-9.52901469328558));
#404=CARTESIAN_POINT('',(-116.054752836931,-55.4006262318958,-9.40477443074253));
#405=CARTESIAN_POINT('',(-114.471222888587,-58.6026857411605,-9.14822402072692));
#406=CARTESIAN_POINT('',(-113.646184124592,-60.1870290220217,-9.01591312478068));
#407=CARTESIAN_POINT('',(-111.931288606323,-63.3191830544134,-8.74419567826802));
#408=CARTESIAN_POINT('',(-111.041445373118,-64.8670013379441,-8.60479060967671));
#409=CARTESIAN_POINT('',(-109.19827857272,-67.9239796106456,-8.31982650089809));
#410=CARTESIAN_POINT('',(-108.244949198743,-69.4331360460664,-8.17426689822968));
#411=CARTESIAN_POINT('',(-106.276635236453,-72.4099830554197,-7.87803690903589));
#412=CARTESIAN_POINT('',(-105.261656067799,-73.8776772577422,-7.72736697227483));
#413=CARTESIAN_POINT('',(-103.171625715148,-76.7694191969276,-7.42193908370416));
#414=CARTESIAN_POINT('',(-102.096568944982,-78.193462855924,-7.26718075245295));
#415=CARTESIAN_POINT('',(-99.8772447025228,-81.0094251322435,-6.95309659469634));
#416=CARTESIAN_POINT('',(-98.7323918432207,-82.4008790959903,-6.79374054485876));
#417=CARTESIAN_POINT('',(-96.3852493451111,-85.13445067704,-6.47307491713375));
#418=CARTESIAN_POINT('',(-95.1829543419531,-86.4765636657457,-6.31176515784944));
#419=CARTESIAN_POINT('',(-92.7231664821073,-89.1089436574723,-5.98835038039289));
#420=CARTESIAN_POINT('',(-91.4656783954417,-90.3992151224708,-5.82624543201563));
#421=CARTESIAN_POINT('',(-88.8975650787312,-92.9258541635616,-5.50236010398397));
#422=CARTESIAN_POINT('',(-87.5869349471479,-94.1622167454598,-5.34057975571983));
#423=CARTESIAN_POINT('',(-83.5786994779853,-97.7871081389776,-4.85743940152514));
#424=CARTESIAN_POINT('',(-80.8042459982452,-100.091978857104,-4.53821324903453));
#425=CARTESIAN_POINT('',(-75.0708880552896,-104.461005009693,-3.91456236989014));
#426=CARTESIAN_POINT('',(-72.1119832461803,-106.52515999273,-3.6101376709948));
#427=CARTESIAN_POINT('',(-66.0084717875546,-110.411976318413,-3.02250712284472));
#428=CARTESIAN_POINT('',(-62.862725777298,-112.232875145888,-2.73946198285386));
#429=CARTESIAN_POINT('',(-56.4262711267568,-115.602846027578,-2.20497321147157));
#430=CARTESIAN_POINT('',(-53.1355616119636,-117.151916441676,-1.95352977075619));
#431=CARTESIAN_POINT('',(-46.4325872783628,-119.966544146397,-1.48941662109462));
#432=CARTESIAN_POINT('',(-43.020329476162,-121.232117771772,-1.27674467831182));
#433=CARTESIAN_POINT('',(-36.0985724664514,-123.470109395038,-0.89624867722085));
#434=CARTESIAN_POINT('',(-32.5890743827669,-124.442530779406,-0.728424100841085));
#435=CARTESIAN_POINT('',(-25.5357021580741,-126.077912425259,-0.443958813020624));
#436=CARTESIAN_POINT('',(-21.9925808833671,-126.744028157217,-0.326796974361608));
#437=CARTESIAN_POINT('',(-14.8617358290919,-127.776579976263,-0.144416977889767));
#438=CARTESIAN_POINT('',(-11.2740123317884,-128.143017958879,-0.0791984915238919));
#439=CARTESIAN_POINT('',(-4.07966106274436,-128.573256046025,-0.00257401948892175));
#440=CARTESIAN_POINT('',(-0.473034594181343,-128.637076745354,0.00883562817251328));
#441=CARTESIAN_POINT('',(4.93027005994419,-128.505592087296,-0.014607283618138));
#442=CARTESIAN_POINT('',(6.73046591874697,-128.423872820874,-0.029185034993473));
#443=CARTESIAN_POINT('',(10.3256342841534,-128.184915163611,-0.0717274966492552));
#444=CARTESIAN_POINT('',(12.1206068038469,-128.027676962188,-0.0996921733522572));
#445=CARTESIAN_POINT('',(17.4522419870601,-127.447402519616,-0.202642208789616));
#446=CARTESIAN_POINT('',(20.9774886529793,-126.914762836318,-0.296874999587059));
#447=CARTESIAN_POINT('',(26.2205295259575,-125.898383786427,-0.474990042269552));
#448=CARTESIAN_POINT('',(27.9609225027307,-125.523302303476,-0.54049836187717));
#449=CARTESIAN_POINT('',(31.4241807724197,-124.701377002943,-0.683299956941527));
#450=CARTESIAN_POINT('',(33.1470461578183,-124.254533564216,-0.760593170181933));
#451=CARTESIAN_POINT('',(38.2849934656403,-122.807403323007,-1.00941111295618));
#452=CARTESIAN_POINT('',(41.6701120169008,-121.700383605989,-1.19789773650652));
#453=CARTESIAN_POINT('',(46.667353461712,-119.833513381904,-1.51051271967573));
#454=CARTESIAN_POINT('',(48.3199101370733,-119.176731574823,-1.61971515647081));
#455=CARTESIAN_POINT('',(51.5958496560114,-117.795464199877,-1.84734216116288));
#456=CARTESIAN_POINT('',(53.2192349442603,-117.070984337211,-1.96576595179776));
#457=CARTESIAN_POINT('',(56.4423886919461,-115.551690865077,-2.21166738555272));
#458=CARTESIAN_POINT('',(58.0419902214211,-114.756530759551,-2.339188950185));
#459=CARTESIAN_POINT('',(61.2061977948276,-113.100552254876,-2.60185801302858));
#460=CARTESIAN_POINT('',(62.7708040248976,-112.239734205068,-2.7370054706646));
#461=CARTESIAN_POINT('',(65.8623778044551,-110.45396834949,-3.01399855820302));
#462=CARTESIAN_POINT('',(67.3893451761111,-109.529020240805,-3.15584421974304));
#463=CARTESIAN_POINT('',(70.4030649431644,-107.616627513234,-3.44525982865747));
#464=CARTESIAN_POINT('',(71.8898174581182,-106.629183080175,-3.59282975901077));
#465=CARTESIAN_POINT('',(74.8208023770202,-104.593388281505,-3.89270187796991));
#466=CARTESIAN_POINT('',(76.2650295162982,-103.545030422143,-4.04500464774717));
#467=CARTESIAN_POINT('',(79.1082324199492,-101.389422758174,-4.35326845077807));
#468=CARTESIAN_POINT('',(80.5072122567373,-100.282178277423,-4.5092291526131));
#469=CARTESIAN_POINT('',(83.257856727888,-98.0104912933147,-4.82376980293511));
#470=CARTESIAN_POINT('',(84.6095168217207,-96.8460433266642,-4.98235000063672));
#471=CARTESIAN_POINT('',(87.2630155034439,-94.4621197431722,-5.30101569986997));
#472=CARTESIAN_POINT('',(88.5648582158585,-93.2426487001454,-5.46110107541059));
#473=CARTESIAN_POINT('',(91.134479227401,-90.7332447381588,-5.78393076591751));
#474=CARTESIAN_POINT('',(92.4015284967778,-89.4425659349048,-5.94668100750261));
#475=CARTESIAN_POINT('',(94.8801024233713,-86.8088775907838,-6.2714647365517));
#476=CARTESIAN_POINT('',(96.0916273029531,-85.465868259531,-6.4334982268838));
#477=CARTESIAN_POINT('',(98.4570780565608,-82.7297971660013,-6.75570494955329));
#478=CARTESIAN_POINT('',(99.6110030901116,-81.3367346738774,-6.91587815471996));
#479=CARTESIAN_POINT('',(101.859216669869,-78.5029699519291,-7.23322397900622));
#480=CARTESIAN_POINT('',(102.953505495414,-77.0622679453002,-7.39039661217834));
#481=CARTESIAN_POINT('',(105.080599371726,-74.1355886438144,-7.70063254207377));
#482=CARTESIAN_POINT('',(106.113400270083,-72.6496083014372,-7.85369556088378));
#483=CARTESIAN_POINT('',(108.115508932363,-69.6351592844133,-8.15459150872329));
#484=CARTESIAN_POINT('',(109.08482266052,-68.1066946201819,-8.30242492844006));
#485=CARTESIAN_POINT('',(110.958406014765,-65.0096384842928,-8.59182677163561));
#486=CARTESIAN_POINT('',(111.86266981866,-63.4410434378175,-8.73339463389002));
#487=CARTESIAN_POINT('',(113.604336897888,-60.2667150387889,-9.00921570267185));
#488=CARTESIAN_POINT('',(114.441746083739,-58.6609849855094,-9.14346955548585));
#489=CARTESIAN_POINT('',(116.04944862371,-55.4126306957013,-9.40389439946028));
#490=CARTESIAN_POINT('',(116.819640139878,-53.7699550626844,-9.53005305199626));
#491=CARTESIAN_POINT('',(118.290061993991,-50.4529243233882,-9.7731435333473));
#492=CARTESIAN_POINT('',(118.990292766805,-48.7785694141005,-9.89007541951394));
#493=CARTESIAN_POINT('',(120.31947933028,-45.4011184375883,-10.1138526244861));
#494=CARTESIAN_POINT('',(120.948434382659,-43.6980220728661,-10.2206978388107));
#495=CARTESIAN_POINT('',(122.13385133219,-40.2661547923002,-10.4235079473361));
#496=CARTESIAN_POINT('',(122.690313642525,-38.5373840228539,-10.5194729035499));
#497=CARTESIAN_POINT('',(123.729652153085,-35.0573242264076,-10.6998053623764));
#498=CARTESIAN_POINT('',(124.212530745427,-33.3060359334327,-10.7841732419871));
#499=CARTESIAN_POINT('',(125.103734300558,-29.7842217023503,-10.940676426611));
#500=CARTESIAN_POINT('',(125.512066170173,-28.0136975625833,-11.0128128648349));
#501=CARTESIAN_POINT('',(126.253435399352,-24.4564162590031,-11.1443228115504));
#502=CARTESIAN_POINT('',(126.586470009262,-22.6696585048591,-11.203695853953));
#503=CARTESIAN_POINT('',(127.176558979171,-19.083254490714,-11.309227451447));
#504=CARTESIAN_POINT('',(127.433613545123,-17.2836082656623,-11.3553860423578));
#505=CARTESIAN_POINT('',(127.868223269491,-13.6995059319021,-11.4335992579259));
#506=CARTESIAN_POINT('',(128.046820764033,-11.9151801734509,-11.465838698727));
#507=CARTESIAN_POINT('',(128.329265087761,-8.34026917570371,-11.5168881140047));
#508=CARTESIAN_POINT('',(128.433105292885,-6.54968339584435,-11.5356968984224));
#509=CARTESIAN_POINT('',(128.565799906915,-2.96574361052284,-11.5597405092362));
#510=CARTESIAN_POINT('',(128.594658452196,-1.17238976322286,-11.5649760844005));
#511=CARTESIAN_POINT('',(128.577344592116,2.41395135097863,-11.5618367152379));
#512=CARTESIAN_POINT('',(128.531171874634,4.20693861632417,-11.5534617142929));
#513=CARTESIAN_POINT('',(128.363890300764,7.78921305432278,-11.5231637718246));
#514=CARTESIAN_POINT('',(128.242785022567,9.57850039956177,-11.501241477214));
#515=CARTESIAN_POINT('',(127.925879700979,13.1502443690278,-11.4440113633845));
#516=CARTESIAN_POINT('',(127.73007916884,14.9327009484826,-11.4087034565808));
#517=CARTESIAN_POINT('',(127.264180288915,18.4874766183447,-11.3249647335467));
#518=CARTESIAN_POINT('',(126.994085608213,20.2597962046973,-11.2765345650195));
#519=CARTESIAN_POINT('',(126.380095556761,23.7913665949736,-11.1669020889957));
#520=CARTESIAN_POINT('',(126.036193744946,25.5506162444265,-11.1056986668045));
#521=CARTESIAN_POINT('',(125.278105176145,29.0397122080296,-10.9714730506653));
#522=CARTESIAN_POINT('',(124.864460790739,30.7696799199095,-10.8985422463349));
#523=CARTESIAN_POINT('',(123.965920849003,34.2104847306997,-10.7410677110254));
#524=CARTESIAN_POINT('',(123.481024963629,35.9213217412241,-10.656523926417));
#525=CARTESIAN_POINT('',(122.440901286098,39.3208659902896,-10.4764309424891));
#526=CARTESIAN_POINT('',(121.885674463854,41.0095735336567,-10.3808818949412));
#527=CARTESIAN_POINT('',(120.705910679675,44.3619875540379,-10.179458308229));
#528=CARTESIAN_POINT('',(120.081373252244,46.0256938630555,-10.0735836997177));
#529=CARTESIAN_POINT('',(118.764134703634,49.3252576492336,-9.85226039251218));
#530=CARTESIAN_POINT('',(118.071433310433,50.9611150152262,-9.73681165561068));
#531=CARTESIAN_POINT('',(116.619062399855,54.2023379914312,-9.49714507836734));
#532=CARTESIAN_POINT('',(115.859387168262,55.8077009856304,-9.37292648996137));
#533=CARTESIAN_POINT('',(114.274542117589,58.9849608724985,-9.11661127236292));
#534=CARTESIAN_POINT('',(113.449377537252,60.5568604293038,-8.9845152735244));
#535=CARTESIAN_POINT('',(111.734880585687,63.664838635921,-8.71334604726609));
#536=CARTESIAN_POINT('',(110.845542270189,65.2009139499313,-8.57427217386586));
#537=CARTESIAN_POINT('',(108.994689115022,68.250401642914,-8.2886384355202));
#538=CARTESIAN_POINT('',(108.032516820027,69.7634091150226,-8.14201550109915));
#539=CARTESIAN_POINT('',(106.045997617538,72.7475388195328,-7.84367692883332));
#540=CARTESIAN_POINT('',(105.021650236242,74.2186607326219,-7.69196125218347));
#541=CARTESIAN_POINT('',(102.912571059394,77.1165309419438,-7.38450347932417));
#542=CARTESIAN_POINT('',(101.827839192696,78.5432791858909,-7.22876137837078));
#543=CARTESIAN_POINT('',(99.5998649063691,81.3499997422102,-6.91434011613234));
#544=CARTESIAN_POINT('',(98.4566224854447,82.7299720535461,-6.75566095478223));
#545=CARTESIAN_POINT('',(96.1134980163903,85.4409196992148,-6.43645942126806));
#546=CARTESIAN_POINT('',(94.9136118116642,86.7718914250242,-6.27593691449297));
#547=CARTESIAN_POINT('',(92.459324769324,89.3824819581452,-5.95417617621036));
#548=CARTESIAN_POINT('',(91.2049242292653,90.6621010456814,-5.79293794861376));
#549=CARTESIAN_POINT('',(88.6436581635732,93.1678966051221,-5.47085392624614));
#550=CARTESIAN_POINT('',(87.3367899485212,94.3940703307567,-5.31000815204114));
#551=CARTESIAN_POINT('',(84.67296524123,96.7907218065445,-4.98984367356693));
#552=CARTESIAN_POINT('',(83.316012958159,97.96120421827,-4.83052484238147));
#553=CARTESIAN_POINT('',(80.5375033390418,100.258386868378,-4.5125908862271));
#554=CARTESIAN_POINT('',(79.1153633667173,101.384386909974,-4.35400754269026));
#555=CARTESIAN_POINT('',(76.2244664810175,103.575408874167,-4.04064120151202));
#556=CARTESIAN_POINT('',(74.7557097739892,104.640431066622,-3.88585818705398));
#557=CARTESIAN_POINT('',(71.7740843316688,106.707623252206,-3.58118447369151));
#558=CARTESIAN_POINT('',(70.261214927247,107.709792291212,-3.43129384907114));
#559=CARTESIAN_POINT('',(67.1940129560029,109.649451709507,-3.13746966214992));
#560=CARTESIAN_POINT('',(65.6396806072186,110.586942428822,-2.99353606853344));
#561=CARTESIAN_POINT('',(62.4922036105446,112.395570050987,-2.71264181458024));
#562=CARTESIAN_POINT('',(60.8990578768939,113.266705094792,-2.57568134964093));
#563=CARTESIAN_POINT('',(57.6769356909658,114.940907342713,-2.30972342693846));
#564=CARTESIAN_POINT('',(56.0479626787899,115.743981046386,-2.18072520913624));
#565=CARTESIAN_POINT('',(52.7567622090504,117.280722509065,-1.93158505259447));
#566=CARTESIAN_POINT('',(51.094531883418,118.014384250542,-1.81144388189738));
#567=CARTESIAN_POINT('',(47.7400501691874,119.410774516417,-1.58089806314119));
#568=CARTESIAN_POINT('',(46.0478015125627,120.073509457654,-1.47049253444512));
#569=CARTESIAN_POINT('',(42.6443992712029,121.323827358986,-1.26070377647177));
#570=CARTESIAN_POINT('',(40.9333764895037,121.911757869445,-1.16126988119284));
#571=CARTESIAN_POINT('',(37.4875043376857,123.015059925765,-0.973522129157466));
#572=CARTESIAN_POINT('',(35.7526551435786,123.530432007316,-0.885208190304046));
#573=CARTESIAN_POINT('',(32.2622189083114,124.487626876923,-0.720328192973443));
#574=CARTESIAN_POINT('',(30.5066317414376,124.929449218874,-0.643762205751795));
#575=CARTESIAN_POINT('',(26.9779086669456,125.738674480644,-0.502925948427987));
#576=CARTESIAN_POINT('',(25.2047728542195,126.106077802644,-0.438655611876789));
#577=CARTESIAN_POINT('',(21.6442161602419,126.765733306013,-0.322871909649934));
#578=CARTESIAN_POINT('',(19.8567957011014,127.057987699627,-0.271358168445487));
#579=CARTESIAN_POINT('',(16.2710468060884,127.566755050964,-0.181458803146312));
#580=CARTESIAN_POINT('',(14.4727193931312,127.783275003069,-0.143071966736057));
#581=CARTESIAN_POINT('',(10.8682216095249,128.140184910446,-0.0796943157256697));
#582=CARTESIAN_POINT('',(9.06205094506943,128.280571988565,-0.0547040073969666));
#583=CARTESIAN_POINT('',(5.44525751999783,128.484921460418,-0.0183014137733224));
#584=CARTESIAN_POINT('',(3.63463477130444,128.548884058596,-0.00688909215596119));
#585=CARTESIAN_POINT('',(0.0375006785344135,128.599899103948,0.002211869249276));
#586=CARTESIAN_POINT('',(-1.74899526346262,128.588010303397,8.94307139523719E-05));
#587=CARTESIAN_POINT('',(-5.32003503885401,128.489817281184,-0.01742318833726));
#588=CARTESIAN_POINT('',(-7.10457868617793,128.403506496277,-0.0328145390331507));
#589=CARTESIAN_POINT('',(-10.6682574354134,128.156636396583,-0.0767576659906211));
#590=CARTESIAN_POINT('',(-12.4473928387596,127.996081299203,-0.105308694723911));
#591=CARTESIAN_POINT('',(-15.9971874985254,127.601036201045,-0.175371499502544));
#592=CARTESIAN_POINT('',(-17.7678467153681,127.366545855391,-0.216883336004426));
#593=CARTESIAN_POINT('',(-21.2974948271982,126.824090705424,-0.312577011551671));
#594=CARTESIAN_POINT('',(-23.0564839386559,126.516127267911,-0.366758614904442));
#595=CARTESIAN_POINT('',(-26.559717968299,125.827315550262,-0.487414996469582));
#596=CARTESIAN_POINT('',(-28.3039627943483,125.446466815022,-0.553889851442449));
#597=CARTESIAN_POINT('',(-31.7745438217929,124.612633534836,-0.698666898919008));
#598=CARTESIAN_POINT('',(-33.5008808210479,124.159652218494,-0.776968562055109));
#599=CARTESIAN_POINT('',(-36.9328502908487,123.182358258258,-0.944865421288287));
#600=CARTESIAN_POINT('',(-38.6384809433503,122.658039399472,-1.03446160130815));
#601=CARTESIAN_POINT('',(-42.0232692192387,121.539959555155,-1.2241735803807));
#602=CARTESIAN_POINT('',(-43.7024640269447,120.946308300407,-1.32427273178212));
#603=CARTESIAN_POINT('',(-47.0343620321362,119.689950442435,-1.53442641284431));
#604=CARTESIAN_POINT('',(-48.6870627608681,119.027237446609,-1.64448186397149));
#605=CARTESIAN_POINT('',(-51.9628970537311,117.634052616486,-1.87377841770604));
#606=CARTESIAN_POINT('',(-53.5860322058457,116.903584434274,-1.9930190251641));
#607=CARTESIAN_POINT('',(-56.8000806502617,115.376175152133,-2.23987538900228));
#608=CARTESIAN_POINT('',(-58.3909937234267,114.579233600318,-2.36749120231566));
#609=CARTESIAN_POINT('',(-61.5379564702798,112.920277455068,-2.63022995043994));
#610=CARTESIAN_POINT('',(-63.0940049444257,112.058260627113,-2.76535314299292));
#611=CARTESIAN_POINT('',(-66.1685807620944,110.270695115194,-3.04218216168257));
#612=CARTESIAN_POINT('',(-67.6871079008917,109.345146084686,-3.18388802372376));
#613=CARTESIAN_POINT('',(-70.6841072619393,107.432130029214,-3.47291805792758));
#614=CARTESIAN_POINT('',(-72.1625792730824,106.444662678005,-3.62024225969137));
#615=CARTESIAN_POINT('',(-75.07700544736,104.40951754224,-3.9195069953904));
#616=CARTESIAN_POINT('',(-76.5129595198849,103.361839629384,-4.0714475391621));
#617=CARTESIAN_POINT('',(-79.3584187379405,101.194007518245,-4.38091942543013));
#618=CARTESIAN_POINT('',(-80.7673342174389,100.073085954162,-4.53849785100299));
#619=CARTESIAN_POINT('',(-83.5366885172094,97.7732401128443,-4.85623414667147));
#620=CARTESIAN_POINT('',(-84.8971275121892,96.594316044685,-5.01639200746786));
#621=CARTESIAN_POINT('',(-87.5672464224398,94.1804735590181,-5.33817364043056));
#622=CARTESIAN_POINT('',(-88.8769255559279,92.9455542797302,-5.49979743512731));
#623=CARTESIAN_POINT('',(-91.443267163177,90.4218602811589,-5.82337930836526));
#624=CARTESIAN_POINT('',(-92.6999299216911,89.1330858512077,-5.98533738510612));
#625=CARTESIAN_POINT('',(-95.1584507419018,86.5034975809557,-6.3085020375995));
#626=CARTESIAN_POINT('',(-96.3602930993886,85.1626690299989,-6.46970838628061));
#627=CARTESIAN_POINT('',(-98.706619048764,82.4317235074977,-6.79017741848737));
#628=CARTESIAN_POINT('',(-99.8511079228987,81.0416110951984,-6.94944027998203));
#629=CARTESIAN_POINT('',(-102.080956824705,78.2142266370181,-7.26492965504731));
#630=CARTESIAN_POINT('',(-103.166312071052,76.7769507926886,-7.42115592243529));
#631=CARTESIAN_POINT('',(-105.275809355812,73.8579144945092,-7.72944194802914));
#632=CARTESIAN_POINT('',(-106.29995665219,72.37615787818,-7.88150206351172));
#633=CARTESIAN_POINT('',(-108.293579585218,69.3580830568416,-8.18163228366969));
#634=CARTESIAN_POINT('',(-109.262530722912,67.821413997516,-8.32965878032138));
#635=CARTESIAN_POINT('',(-111.134708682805,64.7079694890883,-8.61932003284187));
#636=CARTESIAN_POINT('',(-112.03793583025,63.1311942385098,-8.76095482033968));
#637=CARTESIAN_POINT('',(-113.777071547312,59.9401796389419,-9.03681062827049));
#638=CARTESIAN_POINT('',(-114.612975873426,58.3259379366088,-9.17103118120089));
#639=CARTESIAN_POINT('',(-116.215846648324,55.0629297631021,-9.4310650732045));
#640=CARTESIAN_POINT('',(-116.982813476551,53.4141634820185,-9.556878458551));
#641=CARTESIAN_POINT('',(-118.445763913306,50.0863948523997,-9.79907139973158));
#642=CARTESIAN_POINT('',(-119.141806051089,48.4074188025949,-9.91545871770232));
#643=CARTESIAN_POINT('',(-120.462246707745,45.0210486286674,-10.1380447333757));
#644=CARTESIAN_POINT('',(-121.086651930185,43.3136571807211,-10.2442443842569));
#645=CARTESIAN_POINT('',(-122.262616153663,39.873567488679,-10.4456645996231));
#646=CARTESIAN_POINT('',(-122.814185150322,38.1408727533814,-10.5408866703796));
#647=CARTESIAN_POINT('',(-123.843462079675,34.6532594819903,-10.7196514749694));
#648=CARTESIAN_POINT('',(-124.321173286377,32.8983419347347,-10.8031947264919));
#649=CARTESIAN_POINT('',(-125.395673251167,28.5924387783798,-10.9920446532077));
#650=CARTESIAN_POINT('',(-125.952355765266,26.0309736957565,-11.0907506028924));
#651=CARTESIAN_POINT('',(-126.66919642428,22.1670174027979,-11.2184828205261));
#652=CARTESIAN_POINT('',(-126.888435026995,20.8754957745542,-11.2576704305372));
#653=CARTESIAN_POINT('',(-127.287408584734,18.2859795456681,-11.329142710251));
#654=CARTESIAN_POINT('',(-127.467138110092,16.987984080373,-11.361426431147));
#655=CARTESIAN_POINT('',(-127.946674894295,13.0865825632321,-11.4477044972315));
#656=CARTESIAN_POINT('',(-128.186901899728,10.4753757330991,-11.4911385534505));
#657=CARTESIAN_POINT('',(-128.50731763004,5.24271209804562,-11.5491251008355));
#658=CARTESIAN_POINT('',(-128.587494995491,2.62125457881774,-11.5636755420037));
#659=CARTESIAN_POINT('',(-128.5875,0.,-11.5636781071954));
#660=B_SPLINE_CURVE_WITH_KNOTS('',3,(#382,#383,#384,#385,#386,#387,#388,#389,#390,#391,#392,
#393,#394,#395,#396,#397,#398,#399,#400,#401,#402,#403,#404,#405,#406,#407,#408,#409,#410,#411,
#412,#413,#414,#415,#416,#417,#418,#419,#420,#421,#422,#423,#424,#425,#426,#427,#428,#429,#430,
#431,#432,#433,#434,#435,#436,#437,#438,#439,#440,#441,#442,#443,#444,#445,#446,#447,#448,#449,
#450,#451,#452,#453,#454,#455,#456,#457,#458,#459,#460,#461,#462,#463,#464,#465,#466,#467,#468,
#469,#470,#471,#472,#473,#474,#475,#476,#477,#478,#479,#480,#481,#482,#483,#484,#485,#486,#487,
#488,#489,#490,#491,#492,#493,#494,#495,#496,#497,#498,#499,#500,#501,#502,#503,#504,#505,#506,
#507,#508,#509,#510,#511,#512,#513,#514,#515,#516,#517,#518,#519,#520,#521,#522,#523,#524,#525,
#526,#527,#528,#529,#530,#531,#532,#533,#534,#535,#536,#537,#538,#539,#540,#541,#542,#543,#544,
#545,#546,#547,#548,#549,#550,#551,#552,#553,#554,#555,#556,#557,#558,#559,#560,#561,#562,#563,
#564,#565,#566,#567,#568,#569,#570,#571,#572,#573,#574,#575,#576,#577,#578,#579,#580,#581,#582,
#583,#584,#585,#586,#587,#588,#589,#590,#591,#592,#593,#594,#595,#596,#597,#598,#599,#600,#601,
#602,#603,#604,#605,#606,#607,#608,#609,#610,#611,#612,#613,#614,#615,#616,#617,#618,#619,#620,
#621,#622,#623,#624,#625,#626,#627,#628,#629,#630,#631,#632,#633,#634,#635,#636,#637,#638,#639,
#640,#641,#642,#643,#644,#645,#646,#647,#648,#649,#650,#651,#652,#653,#654,#655,#656,#657,#658,
#659),.UNSPECIFIED.,.T.,.F.,(4,2,2,2,2,2,2,2,2,2,2,2,2,2,2,2,2,2,2,2,2,2,2,2,2,2,2,2,2,2,2,2,2,
2,2,2,2,2,2,2,2,2,2,2,2,2,2,2,2,2,2,2,2,2,2,2,2,2,2,2,2,2,2,2,2,2,2,2,2,2,2,2,2,2,2,2,2,2,2,2,2,
2,2,2,2,2,2,2,2,2,2,2,2,2,2,2,2,2,2,2,2,2,2,2,2,2,2,2,2,2,2,2,2,2,2,2,2,2,2,2,2,2,2,2,2,2,2,2,2,
2,2,2,2,2,2,2,2,2,4),(0.,5.37174868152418,10.7427886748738,16.1150994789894,21.4875972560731,
26.86429773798,32.2410262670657,37.6174813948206,42.9939481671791,48.3654064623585,
53.7373327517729,59.1088223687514,64.480810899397,69.8516817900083,75.2230446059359,
80.5939359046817,85.9653274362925,91.3905213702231,96.8162229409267,102.241456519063,
107.667191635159,118.516449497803,129.365727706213,140.289782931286,151.21390406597,
162.137395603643,173.060760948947,183.868926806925,194.677024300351,205.484386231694,
210.8892714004,216.294143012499,226.978637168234,232.322030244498,237.665395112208,
248.350035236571,253.693784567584,259.037083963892,264.40819834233,269.779284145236,
275.150395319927,280.521490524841,285.893247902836,291.264520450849,296.636306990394,
302.00764781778,307.453956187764,312.900242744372,318.346608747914,323.792949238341,
329.239657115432,334.685852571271,340.132534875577,345.578735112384,351.033048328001,
356.487327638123,361.941663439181,367.395968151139,372.850095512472,378.303717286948,
383.757538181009,389.211344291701,394.590324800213,399.969781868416,405.348942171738,
410.728124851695,416.107050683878,421.486011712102,426.864707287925,432.243872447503,
437.582986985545,442.922126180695,448.261191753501,453.600293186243,458.939415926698,
464.278994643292,469.618146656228,474.957793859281,480.353273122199,485.748793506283,
491.144320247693,496.539847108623,501.93577051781,507.331664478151,512.7278353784,
518.123553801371,523.584490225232,529.045402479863,534.506397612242,539.967364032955,
545.428483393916,550.889080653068,556.350150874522,561.810726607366,567.244925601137,
572.679084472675,578.113276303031,583.547438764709,588.981441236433,594.414941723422,
599.848647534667,605.282338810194,610.640352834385,615.998839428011,621.357021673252,
626.71522891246,632.07333648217,637.431477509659,642.789378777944,648.147747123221,
653.497746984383,658.848242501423,664.198449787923,669.548693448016,674.899120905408,
680.249577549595,685.600062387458,690.950558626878,696.370875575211,701.791172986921,
707.21155384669,712.631905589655,718.053800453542,723.475195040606,728.897027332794,
734.318393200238,739.784769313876,745.251118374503,750.717811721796,756.184474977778,
761.646589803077,767.10819308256,772.569046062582,778.029656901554,785.893216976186,
789.824452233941,793.756227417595,801.618602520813,809.481535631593),.UNSPECIFIED.);
#661=CARTESIAN_POINT('',(-128.5875,0.,-11.5636781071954));
#662=VERTEX_POINT('',#661);
#663=EDGE_CURVE('E37',#662,#662,#660,.T.);
#664=ORIENTED_EDGE('',*,*,#663,.F.);
#665=EDGE_LOOP('',(#664));
#666=FACE_BOUND('',#665,.T.);
#667=ORIENTED_EDGE('',*,*,#31,.T.);
#668=EDGE_LOOP('',(#667));
#669=FACE_BOUND('',#668,.T.);
#670=ADVANCED_FACE('F62',(#666,#669),#381,.F.);
#671=CARTESIAN_POINT('',(0.,-134.9375,-720.725));
#672=DIRECTION('',(0.,1.,0.));
#673=DIRECTION('',(0.,0.,1.));
#674=AXIS2_PLACEMENT_3D('',#671,#672,#673);
#675=CYLINDRICAL_SURFACE('',#674,720.725);
#676=ORIENTED_EDGE('',*,*,#663,.T.);
#677=EDGE_LOOP('',(#676));
#678=FACE_BOUND('',#677,.T.);
#679=ORIENTED_EDGE('',*,*,#361,.F.);
#680=EDGE_LOOP('',(#679));
#681=FACE_BOUND('',#680,.T.);
#682=ADVANCED_FACE('F57',(#678,#681),#675,.F.);
#683=CARTESIAN_POINT('',(0.,0.,63.5));
#684=DIRECTION('',(0.,0.,-1.));
#685=DIRECTION('',(-1.,0.,0.));
#686=AXIS2_PLACEMENT_3D('',#683,#684,#685);
#687=CONICAL_SURFACE('',#686,130.175,0.654498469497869);
#688=ORIENTED_EDGE('',*,*,#372,.T.);
#689=EDGE_LOOP('',(#688));
#690=FACE_BOUND('',#689,.T.);
#691=ORIENTED_EDGE('',*,*,#42,.F.);
#692=EDGE_LOOP('',(#691));
#693=FACE_BOUND('',#692,.T.);
#694=ADVANCED_FACE('F61',(#690,#693),#687,.T.);
#695=CLOSED_SHELL('',(#46,#376,#670,#682,#694));
#696=MANIFOLD_SOLID_BREP('B2',#695);
#697=ADVANCED_BREP_SHAPE_REPRESENTATION('',(#18,#696),#14);
#698=SHAPE_DEFINITION_REPRESENTATION(#9,#697);
ENDSEC;
END-ISO-10303-21;
